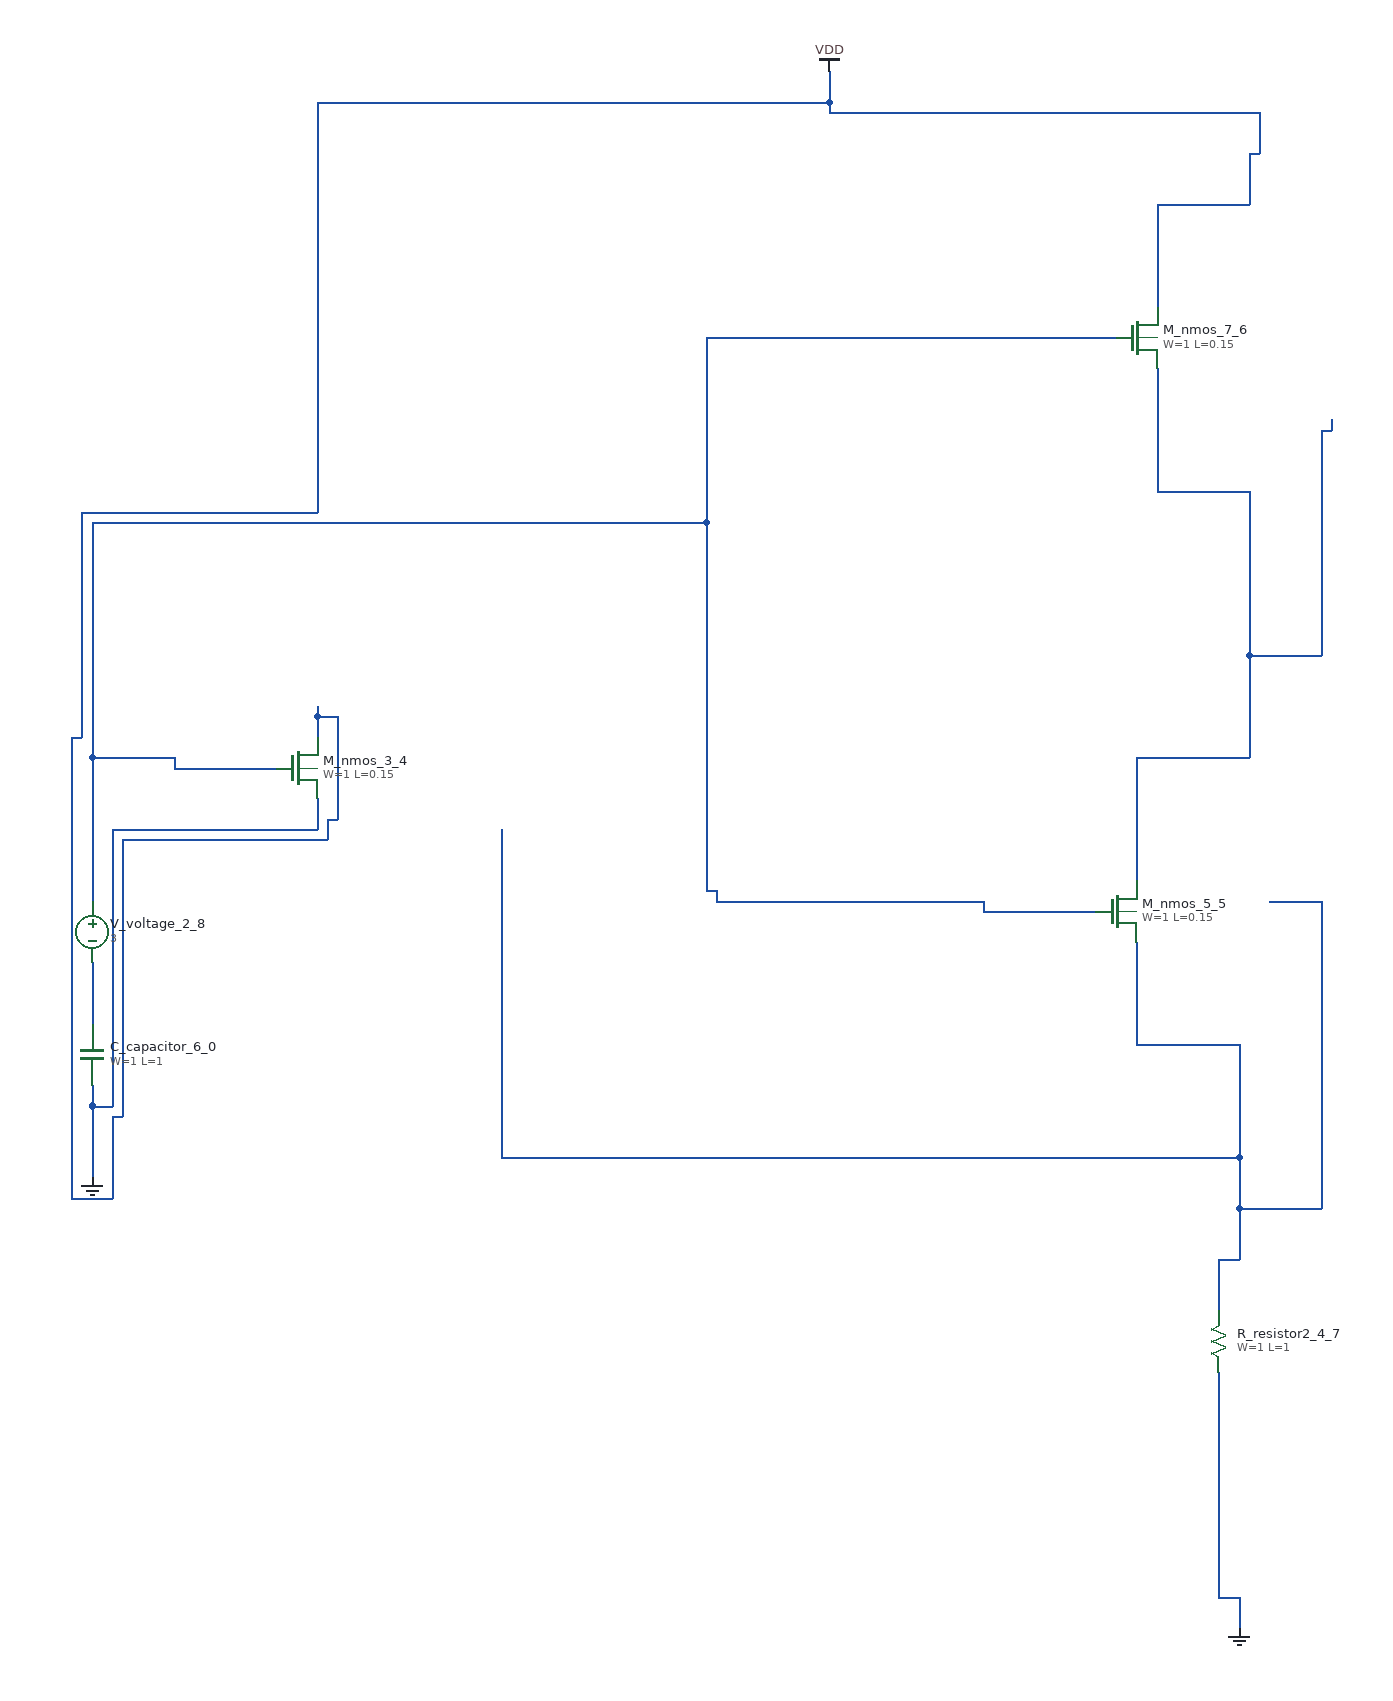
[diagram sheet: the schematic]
v {xschem version=3.4.8 file_version=1.2}
G {}
K {}
V {}
S {}
E {}
C {sky130_fd_pr/cap_mim_m3_1.sym} 240 1080 2 0 {name="C_capacitor_6_0" model=cap_mim_m3_1 W=1 L=1 MF=1 spiceprefix=X}
C {devices/vdd.sym} 960 120 0 0 {name="l_gnd_0_1" lab="VDD"}
C {devices/gnd.sym} 1360 1640 0 0 {name="l_gnd_1_2" lab="GND"}
C {devices/gnd.sym} 240 1200 0 0 {name="l_gnd_8_3" lab="GND"}
C {sky130_fd_pr/nfet3_01v8.sym} 440 800 0 0 {name="M_nmos_3_4"
W=1
L=0.15
body=GND
nf=1
mult=1
ad="expr('int((@nf + 1)/2) * @W / @nf * 0.29')"
pd="expr('2*int((@nf + 1)/2) * (@W / @nf + 0.29)')"
as="expr('int((@nf + 2)/2) * @W / @nf * 0.29')"
ps="expr('2*int((@nf + 2)/2) * (@W / @nf + 0.29)')"
nrd="expr('0.29 / @W ')" nrs="expr('0.29 / @W ')"
sa=0 sb=0 sd=0
model=nfet_01v8
spiceprefix=X
}
C {sky130_fd_pr/nfet3_01v8.sym} 1240 940 0 0 {name="M_nmos_5_5"
W=1
L=0.15
body=GND
nf=1
mult=1
ad="expr('int((@nf + 1)/2) * @W / @nf * 0.29')"
pd="expr('2*int((@nf + 1)/2) * (@W / @nf + 0.29)')"
as="expr('int((@nf + 2)/2) * @W / @nf * 0.29')"
ps="expr('2*int((@nf + 2)/2) * (@W / @nf + 0.29)')"
nrd="expr('0.29 / @W ')" nrs="expr('0.29 / @W ')"
sa=0 sb=0 sd=0
model=nfet_01v8
spiceprefix=X
}
C {sky130_fd_pr/nfet3_01v8.sym} 1260 380 0 0 {name="M_nmos_7_6"
W=1
L=0.15
body=GND
nf=1
mult=1
ad="expr('int((@nf + 1)/2) * @W / @nf * 0.29')"
pd="expr('2*int((@nf + 1)/2) * (@W / @nf + 0.29)')"
as="expr('int((@nf + 2)/2) * @W / @nf * 0.29')"
ps="expr('2*int((@nf + 2)/2) * (@W / @nf + 0.29)')"
nrd="expr('0.29 / @W ')" nrs="expr('0.29 / @W ')"
sa=0 sb=0 sd=0
model=nfet_01v8
spiceprefix=X
}
C {sky130_fd_pr/res_generic_po.sym} 1340 1360 2 0 {name="R_resistor2_4_7"
W=1
L=1
model=res_generic_po
spiceprefix=X
mult=1}
C {devices/vsource.sym} 240 960 0 0 {name="V_voltage_2_8" value=3 savecurrent=false}
N 240 1050 240 990 {}
N 1340 1610 1360 1610 {}
N 240 1130 260 1130 {}
N 260 860 460 860 {}
N 240 1200 240 1130 {}
N 240 1130 240 1110 {}
N 260 1130 260 860 {}
N 460 860 460 830 {}
N 1340 1610 1340 1390 {}
N 1360 1640 1360 1610 {}
N 220 1220 260 1220 {}
N 260 1140 270 1140 {}
N 270 870 470 870 {}
N 470 850 480 850 {}
N 220 770 230 770 {}
N 460 750 480 750 {}
N 230 550 460 550 {}
N 1280 250 1370 250 {}
N 1370 200 1380 200 {}
N 960 160 1380 160 {}
N 460 150 960 150 {}
N 220 1220 220 770 {}
N 230 770 230 550 {}
N 260 1220 260 1140 {}
N 270 1140 270 870 {}
N 460 770 460 750 {}
N 460 750 460 740 {}
N 460 550 460 150 {}
N 470 870 470 850 {}
N 480 850 480 750 {}
N 960 160 960 150 {}
N 960 150 960 120 {}
N 1280 350 1280 250 {}
N 1370 250 1370 200 {}
N 1380 200 1380 160 {}
N 1110 940 1220 940 {}
N 850 930 1110 930 {}
N 840 920 850 920 {}
N 320 800 420 800 {}
N 240 790 320 790 {}
N 240 560 840 560 {}
N 840 380 1240 380 {}
N 240 930 240 790 {}
N 240 790 240 560 {}
N 320 800 320 790 {}
N 840 920 840 560 {}
N 840 560 840 380 {}
N 850 930 850 920 {}
N 1110 940 1110 930 {}
N 1260 790 1370 790 {}
N 1370 690 1440 690 {}
N 1280 530 1370 530 {}
N 1440 470 1450 470 {}
N 1260 910 1260 790 {}
N 1280 530 1280 410 {}
N 1370 790 1370 690 {}
N 1370 690 1370 530 {}
N 1440 690 1440 470 {}
N 1450 470 1450 460 {}
N 1340 1280 1360 1280 {}
N 1360 1230 1440 1230 {}
N 640 1180 1360 1180 {}
N 1260 1070 1360 1070 {}
N 1390 930 1440 930 {}
N 640 1180 640 860 {}
N 1260 1070 1260 970 {}
N 1340 1330 1340 1280 {}
N 1360 1280 1360 1230 {}
N 1360 1230 1360 1180 {}
N 1360 1180 1360 1070 {}
N 1440 1230 1440 930 {}
